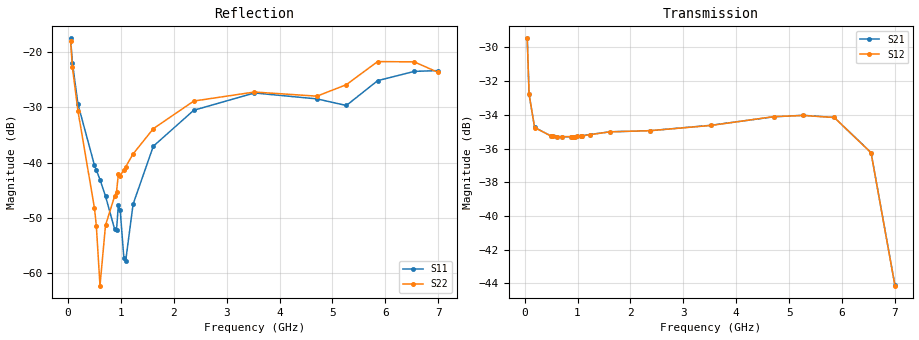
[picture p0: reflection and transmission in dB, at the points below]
! Integrated Device Technology
! Corporate Headquarters
! 6024 Silver Creek Valley Road
! San Jose, CA 95138  USA
! Phone:  1-408-284-8200
! Toll Free:  1-800-223-1366
! Webpage:  http://www.idt.com/
! Timing and RF Division
! 515 Groton Road, Suite 102
! Westford, MA 01886-6024
! Device:  F2258
! Description: Voltage Variable RF Attenuator
! Frequency:  50.0 -  6000.00 MHz
! Package:  3x3 mm Thin QFN Plastic Package: 16 pin
! Ports:  2 RF, 2 DC
!  Pin  1  = NC
!  Pin  2  = NC
!  Pin  3  = RF2  = Port 2
!  Pin  4  = GND
!  Pin  5  = Vdd
!  Pin  6  = NC
!  Pin  7  = VCTRL
!  Pin  8  = NC
!  Pin  9  = GND
!  Pin 10  = RF1  = Port 1
!  Pin 11  = NC
!  Pin 12  = NC
!  Pin 13  = NC
!  Pin 14  = NC
!  Pin 15  = NC
!  Pin 16  = NC
! Vcntrl:  2.140 Volts
! Vdd:  +3.300 Volts
! Current:  1.150 mA
! Data:  The device was measured on a the F2258 evaluation board which has
!  individual transmission lines to the RF pins.  Data was collected
!  using a calibrated network analyzer.  The evaluation board was
!  de-embedded using a TRL calibration technique.
!  The reference plane is the edge of the package pin.
! Misc:  SN 10
!  Action Tracker AT0285
! Date Measured:  2014-12-10
! Date:  2016-01-13  MJV
! Note:
!  Integrated Device Technology supplies this data as a sample of measured
!  data at the package pin for this product.  Your particular data for this
!  product may vary.
!  Data was taken at 25 degrees C.
!  Integrated Device Technology reserves the right to change this data at anytime.
!Freq_(GHz)  S11M_(dB)  S11P_(deg)  S21M_(dB)  S21P_(deg)  S12M_(dB)  S12P_(deg)  S22M_(dB)  S22P_(deg)
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# GHz S dB R 50
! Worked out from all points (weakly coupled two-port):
!   201 points, 50 MHz to 7 GHz, reference 50 ohm
!   highest |S21| = -29.47 dB at 50 MHz (marker M1); lowest = -44.1 dB at 7 GHz (marker M2)
!   lowest |S11| = -57.7 dB at 1.093 GHz (marker M3), VSWR 1.00, Z = 49.9 + j0.113 ohm
!   |S11| at or under -10 dB: start of sweep to end of sweep
!   |S22| runs from -62.2 to -18.0 dB; largest |S21 - S12| = 6.9e-05
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0.05  -17.55 -111.0  -29.47 -67.9  -29.47 -67.9  -18.05 -110.4
0.08475  -21.98 -107.4  -32.78 -48.2  -32.78 -48.2  -22.79 -105.0
0.189  -29.41 -109.4  -34.75 -24.5  -34.76 -24.5  -30.63 -102.5
0.50175  -40.48 -121.8  -35.26 -11.2  -35.26 -11.2  -48.22 -91.6
0.5365  -41.32 -123.6  -35.27 -10.8  -35.27 -10.7  -51.35 -81.0
0.606  -43.05 -125.9  -35.29 -10.0  -35.29 -10.0  -62.21 -36.4
0.71025  -46.04 -137.5  -35.30 -9.2  -35.30 -9.2  -51.30 67.4
0.884  -52.06 166.3  -35.30 -8.5  -35.29 -8.5  -46.00 77.1
0.91875  -52.11 151.3  -35.29 -8.4  -35.29 -8.4  -45.25 77.9
0.9535  -47.56 -163.3  -35.30 -8.3  -35.30 -8.3  -42.04 99.7
0.98825  -48.61 -174.4  -35.28 -8.2  -35.28 -8.2  -42.36 96.0
1.05775  -57.28 153.5  -35.26 -8.1  -35.26 -8.1  -41.24 80.5
1.0925  -57.67 120.0  -35.25 -8.0  -35.25 -8.0  -40.72 77.1
1.2315  -47.49 46.4  -35.17 -8.1  -35.18 -8.1  -38.42 59.3
1.61375  -37.03 32.8  -35.01 -9.8  -35.01 -9.8  -33.86 42.0
2.37825  -30.53 48.1  -34.94 -13.4  -34.94 -13.5  -28.87 37.0
3.525  -27.41 91.6  -34.62 -20.0  -34.63 -20.0  -27.24 62.9
4.7065  -28.48 95.7  -34.12 -29.2  -34.11 -29.1  -27.99 54.4
5.2625  -29.67 54.3  -34.03 -35.3  -34.04 -35.3  -25.91 17.0
5.85325  -25.19 29.9  -34.16 -45.8  -34.16 -45.8  -21.74 -5.2
6.54825  -23.51 45.0  -36.24 -66.4  -36.25 -66.5  -21.80 -39.8
7  -23.37 84.5  -44.11 -61.9  -44.13 -61.5  -23.71 -129.2
